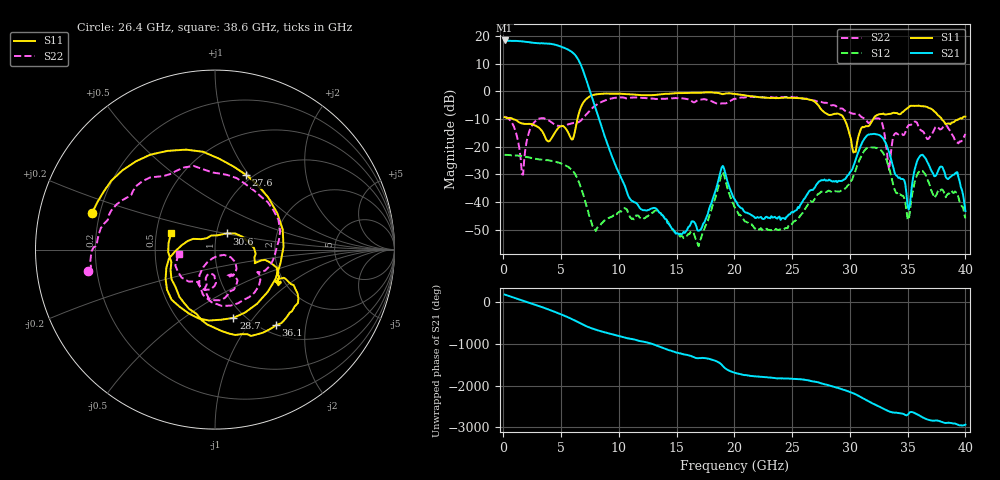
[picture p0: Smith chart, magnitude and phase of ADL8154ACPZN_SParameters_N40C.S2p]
! Analog Devices, Inc."
! Device:	ADL8154ACPZN
! Description:	"10 MHz to 6 GHz, Wideband, Low Noise Amplifier"
! Conditions:	Vdd = 5.0 V
!		IDQ = 125 mA
!		Pin = -25 dBm
!		Operating Temperature = -40 C (at package bottom)
! Product validation unit SN30 soldered down to Evaluation Board as shown on ADL8154-EVALZ User Guide. Board loss de-embedded from S21 magnitude.  All other RF measurements reference to RF coaxial connector.
! Frequency (GHz)	S11_Mag (dB)	S11_Phase (deg)	S21_Mag (dB)	S21_Phase (deg)	S12_Mag (dB)	S12_Phase (deg)	S22_Mag (dB)	S22_Phase (deg)
#  GHZ  S  DB  R 50
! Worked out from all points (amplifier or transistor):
!   400 points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, 110 MHz to 40 GHz, reference 50 ohm
!   highest |S21| = 18.4 dB at 110 MHz (marker M1)
!   |S21| within 3 dB of that: start of sweep to 5.45 GHz
!   unconditionally stable (mu >= 1): start of sweep to end of sweep
!   at 6.708 GHz: K = 5.94, MAG = 11.5 dB, |S12| = -34.7 dB
!   at 20.11 GHz: K = 587.79, MAG = -29.3 dB, |S12| = -42.4 dB
!   at 40 GHz: K = 12408.48, MAG = -42.6 dB, |S12| = -46.0 dB
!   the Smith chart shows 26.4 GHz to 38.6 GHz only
!   S11 on the Smith chart (normalised r, x): 26.4 GHz: 0.17, +0.14; 27.6 GHz: 0.93, +0.97; 28.7 GHz: 0.89, -0.80; 30.6 GHz: 1.12, +0.20; 36.1 GHz: 1.15, -1.37; 38.6 GHz: 0.60, +0.12
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0.11  -9.33 -179.1  18.42 170.8  -22.95 -5.7  -9.21 169.4
1.01  -10.25 138.6  18.28 88.2  -23.16 -73.0  -13.87 90.7
1.91  -11.80 110.2  17.94 5.1  -23.68 -141.1  -20.74 -136.9
2.309  -11.79 94.8  17.74 -31.6  -23.98 -172.1  -13.78 -178.3
2.909  -12.67 53.3  17.47 -86.9  -24.50 141.5  -10.22 137.7
3.809  -17.93 -63.6  17.32 -174.4  -24.96 69.3  -10.29 74.3
4.609  -14.04 151.9  16.73 101.1  -25.58 -0.1  -12.29 13.5
5.409  -13.51 59.7  15.50 10.8  -26.82 -74.1  -12.33 -68.8
6.108  -16.18 -99.5  13.65 -78.2  -29.30 -148.9  -11.38 -143.6
6.808  -4.88 134.6  8.59 -177.0  -35.98 125.5  -10.15 162.6
7.908  -1.17 41.5  -5.24 60.6  -49.62 -16.6  -5.36 75.6
13.407  -1.22 172.8  -43.31 17.6  -43.46 16.9  -2.76 170.2
20.105  -0.97 7.5  -39.66 99.7  -42.42 99.3  -2.68 -12.6
26.403  -2.91 163.7  -36.60 -76.9  -40.67 -79.8  -2.88 -170.5
26.803  -3.37 139.3  -35.66 -101.1  -39.90 -102.3  -3.20 -177.1
27.603  -6.92 67.4  -32.13 -154.9  -36.29 -157.6  -3.96 166.8
28.703  -8.10 -74.9  -32.64 123.1  -36.20 121.7  -5.10 136.7
30.602  -19.08 54.3  -23.42 -64.3  -27.21 -63.4  -8.13 33.9
33.402  -8.15 -26.2  -22.08 -98.1  -27.81 -98.7  -28.43 -70.0
36.101  -5.33 -51.2  -23.24 150.7  -28.59 151.5  -13.90 -103.5
38.6  -11.64 159.7  -31.34 -10.4  -36.97 4.1  -13.82 -173.4
40  -9.16 62.4  -43.31 -53.9  -45.95 -39.3  -15.43 149.2
